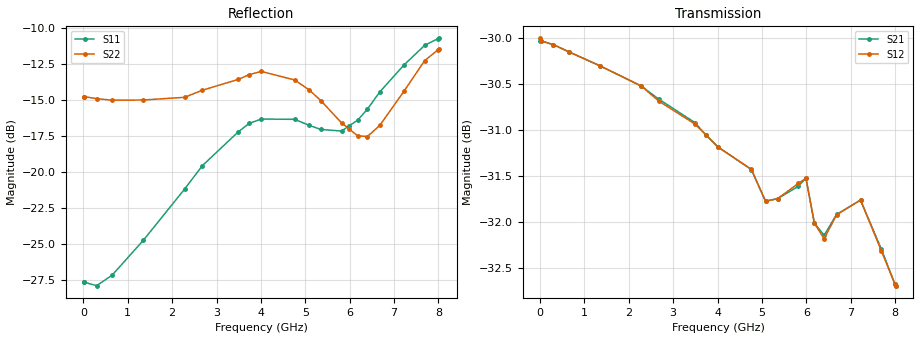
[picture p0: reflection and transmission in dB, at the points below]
! DEVICE ID: PE43712
! File Path: z:\PE43713\PE43713_CHAR_NOM_04292014\AMB\3p300\LS_ATT_28p75dB\PE43713_AMB_3p300V_3p000V_0p000V_LS_ATT_28p75dB_S2P_SN_10_A0139A.s2p
! Serial: 10
! Lot: A0139A
! Temp: 25C
! VDD: 3.300
! VSS: 0.000
! Control_Hi: 3.000
! Control_Lo: 0.000
! Attenuation Step: 28.75dB
! Port 1: RF1
! Port 2: RF2
! ThroughPath:1-2
! IDD: 0.0001455546
! ISS: -1.843e-007
#  Hz  S  RI  R  50
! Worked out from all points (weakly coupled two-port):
!   801 points, 10 MHz to 8.01 GHz, reference 50 ohm
!   highest |S21| = -30.02 dB at 20 MHz (marker M1); lowest = -32.7 dB at 7.99 GHz (marker M2)
!   lowest |S11| = -27.9 dB at 300 MHz (marker M3), VSWR 1.08, Z = 46.3 + j1.27 ohm
!   |S11| at or under -10 dB: start of sweep to end of sweep
!   |S22| runs from -17.5 to -11.5 dB; largest |S21 - S12| = 0.00013
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1e7  -0.0416 0.000878  0.0315 -0.000143  0.0316 -0.000114  -0.1832 0.00121
2e7  -0.0414 0.00159  0.0315 -0.000227  0.0315 -0.000223  -0.183 0.00217
3e8  -0.0379 0.0137  0.0312 -0.0031  0.0312 -0.00309  -0.1789 0.0207
6.5e8  -0.0337 0.0281  0.0304 -0.00642  0.0304 -0.00642  -0.1727 0.0428
1.35e9  -0.021 0.054  0.0279 -0.0124  0.0279 -0.0124  -0.1568 0.0846
2.28e9  0.0095 0.0868  0.023 -0.0189  0.023 -0.0189  -0.119 0.1378
2.68e9  0.025 0.1023  0.0203 -0.0211  0.0203 -0.021  -0.0987 0.1655
3.49e9  0.0483 0.1294  0.0146 -0.0244  0.0145 -0.0244  -0.0692 0.1984
3.74e9  0.0533 0.1379  0.0126 -0.025  0.0126 -0.025  -0.0647 0.2087
4.01e9  0.0582 0.1415  0.0105 -0.0255  0.0105 -0.0255  -0.0614 0.2154
4.76e9  0.0721 0.1345  0.00522 -0.0263  0.00525 -0.0263  -0.0409 0.2051
5.08e9  0.0815 0.1207  0.00293 -0.0256  0.00298 -0.0256  -0.0307 0.1911
5.35e9  0.0911 0.1073  0.00162 -0.0258  0.00159 -0.0258  -0.021 0.1761
5.82e9  0.1142 0.0792  -0.00166 -0.0262  -0.00162 -0.0263  0.0148 0.1474
5.99e9  0.1268 0.0704  -0.00347 -0.0263  -0.00342 -0.0263  0.0315 0.1377
6.18e9  0.1394 0.0596  -0.00486 -0.0246  -0.00483 -0.0246  0.0522 0.1231
6.4e9  0.1573 0.0521  -0.00491 -0.0242  -0.00486 -0.0241  0.0778 0.1079
6.68e9  0.1852 0.0435  -0.00649 -0.0245  -0.00644 -0.0245  0.1121 0.0928
7.22e9  0.2329 0.0355  -0.0113 -0.0232  -0.0113 -0.0232  0.1714 0.084
7.69e9  0.2733 0.039  -0.0133 -0.0203  -0.0132 -0.0203  0.2268 0.0908
7.99e9  0.288 0.0424  -0.0142 -0.0184  -0.0142 -0.0184  0.2489 0.0946
8.01e9  0.2886 0.0434  -0.0141 -0.0184  -0.0141 -0.0184  0.25 0.0944
